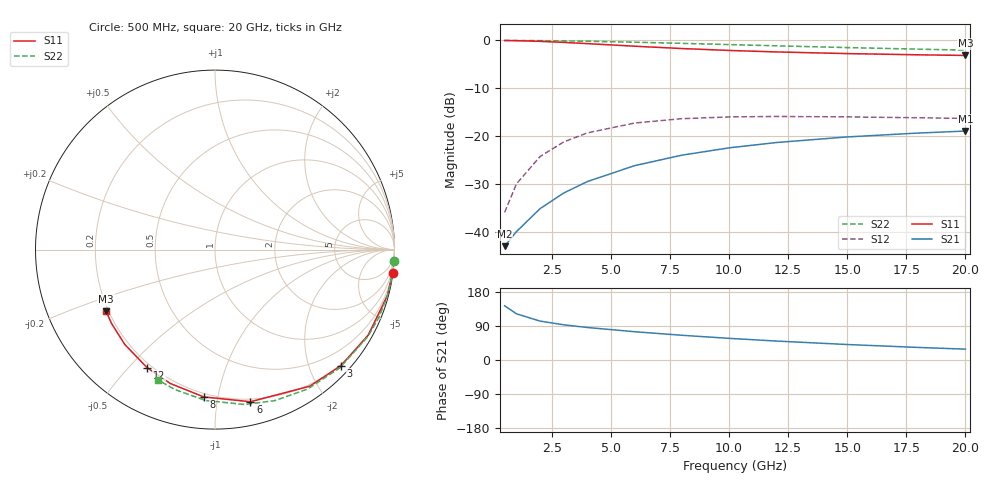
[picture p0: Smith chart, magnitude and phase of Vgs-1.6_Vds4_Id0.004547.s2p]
# Hz S RI R 50
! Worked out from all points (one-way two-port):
!   12 points, 500 MHz to 20 GHz, reference 50 ohm
!   highest |S21| = -18.89 dB at 20 GHz (marker M1); lowest = -42.9 dB at 500 MHz (marker M2)
!   lowest |S11| = -3.1 dB at 20 GHz (marker M3), VSWR 5.61, Z = 9.51 - j12.7 ohm
!   |S11| at or under -10 dB: nowhere
!   |S22| runs from -2.0 to 0.0 dB; largest |S21 - S12| = 0.12
!   S11 on the Smith chart (normalised r, x): 500 MHz: 0, -15; 3 GHz: 0.18, -2.55; 6 GHz: 0.18, -1.24; 8 GHz: 0.18, -0.91; 12 GHz: 0.18, -0.56; 20 GHz: 0.19, -0.25
5e8  0.9901 -0.1292  -0.00574 0.00432  0.00153 0.0161  0.9971 -0.0657
1e9  0.9611 -0.2541  -0.00538 0.00863  0.00601 0.0314  0.9897 -0.1309
2e9  0.8538 -0.4765  -0.00388 0.0172  0.0224 0.0575  0.9605 -0.2577
3e9  0.701 -0.6471  -0.00128 0.0257  0.0452 0.075  0.9136 -0.3764
4e9  0.5282 -0.761  0.00249 0.0337  0.0699 0.0833  0.8516 -0.4845
6e9  0.1976 -0.8477  0.0131 0.0478  0.113 0.0788  0.6948 -0.6596
8e9  -0.0628 -0.8207  0.0267 0.0579  0.1408 0.0598  0.5151 -0.7771
1e10  -0.2489 -0.746  0.0412 0.0638  0.155 0.0382  0.3342 -0.8413
1.2e10  -0.3786 -0.6576  0.0555 0.0661  0.1603 0.0188  0.1653 -0.863
1.5e10  -0.5032 -0.5276  0.0747 0.0646  0.1597 -0.00376  -0.0523 -0.8407
1.8e10  -0.5763 -0.4117  0.0907 0.0593  0.1551 -0.0195  -0.2239 -0.7794
2e10  -0.6072 -0.3429  0.0997 0.0545  0.1516 -0.0273  -0.3153 -0.7273
